VERSION 5.8 ;
BUSBITCHARS "[]" ;
DIVIDERCHAR "/" ;
UNITS
  DATABASE MICRONS 1000 ;
END UNITS
MANUFACTURINGGRID 0.005 ;
PROPERTYDEFINITIONS
  VIA OR_DEFAULT STRING ;
END PROPERTYDEFINITIONS
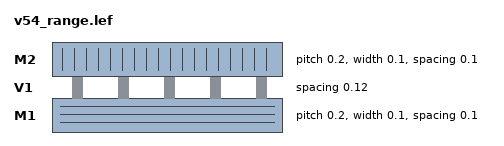
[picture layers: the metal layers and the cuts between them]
LAYER M1
  TYPE ROUTING ;
  DIRECTION HORIZONTAL ;
  PITCH 0.2 ;
  WIDTH 0.1 ;
  SPACING 0.1 ;
  SPACING 0.15 RANGE 0.3 0.6 ;
END M1
LAYER V1
  TYPE CUT ;
  SPACING 0.12 ;
END V1
LAYER M2
  TYPE ROUTING ;
  DIRECTION VERTICAL ;
  PITCH 0.2 ;
  WIDTH 0.1 ;
  SPACING 0.1 RANGE 0.1 0.2 ;
END M2
VIA V1_A DEFAULT
  LAYER M1 ;
    RECT -0.05 -0.05 0.05 0.05 ;
  LAYER V1 ;
    RECT -0.03 -0.03 0.03 0.03 ;
  LAYER M2 ;
    RECT -0.05 -0.05 0.05 0.05 ;
END V1_A
VIA V1_B DEFAULT
  PROPERTY OR_DEFAULT "1" ;
  LAYER M1 ;
    RECT -0.06 -0.05 0.06 0.05 ;
  LAYER V1 ;
    RECT -0.03 -0.03 0.03 0.03 ;
  LAYER M2 ;
    RECT -0.05 -0.06 0.05 0.06 ;
END V1_B
SITE core
  CLASS CORE ;
  SIZE 0.2 BY 1.4 ;
END core
MACRO filler
  CLASS CORE ;
  SIZE 0.2 BY 1.4 ;
  SITE core ;
END filler
END LIBRARY
